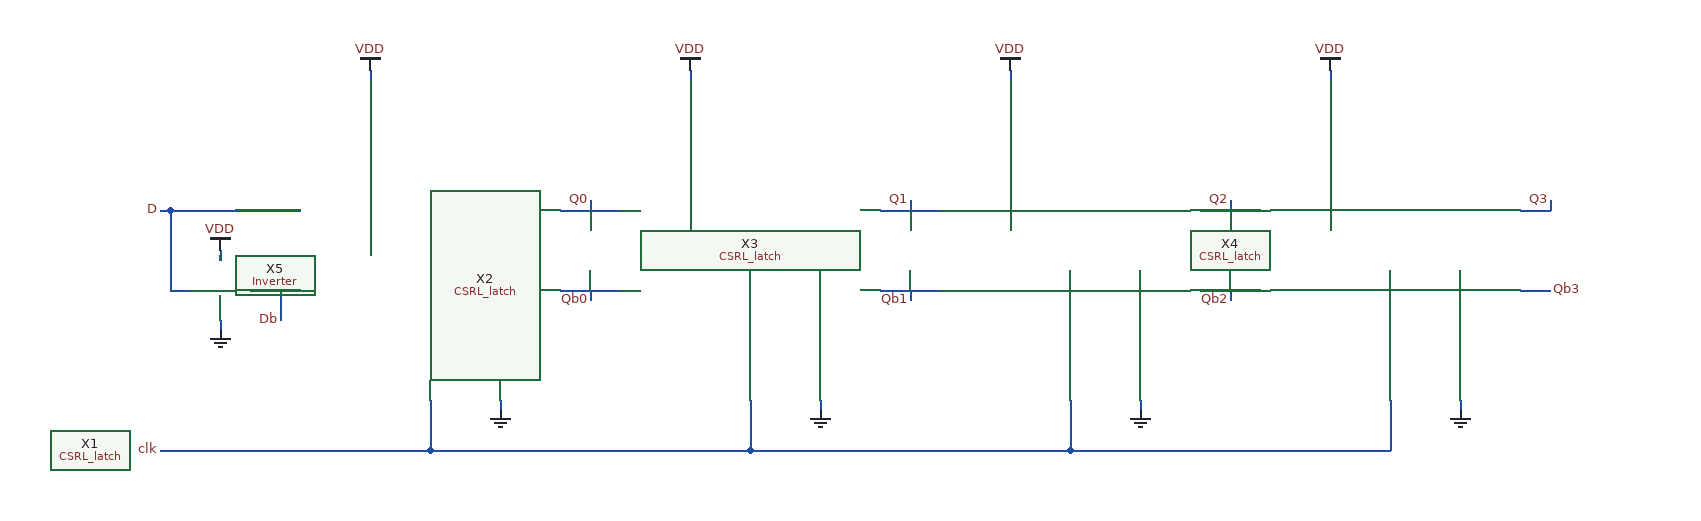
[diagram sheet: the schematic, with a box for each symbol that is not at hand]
v {xschem version=2.9.9 file_version=1.2 }
G {}
K {}
V {}
S {}
E {}
N 280 -440 320 -440 { lab=Db}
N 270 -440 280 -440 { lab=Db}
N 300 -440 300 -410 { lab=Db}
N 190 -440 210 -440 { lab=D}
N 240 -480 240 -470 { lab=VDD}
N 240 -410 240 -400 { lab=GND}
N 190 -520 190 -440 { lab=D}
N 190 -520 320 -520 { lab=D}
N 180 -520 190 -520 { lab=D}
N 580 -440 640 -440 { lab=Qb0}
N 610 -440 610 -430 { lab=Qb0}
N 580 -520 640 -520 { lab=Q0}
N 610 -530 610 -520 { lab=Q0}
N 390 -660 390 -650 { lab=VDD}
N 710 -660 710 -650 { lab=VDD}
N 520 -330 520 -320 { lab=GND}
N 840 -330 840 -320 { lab=GND}
N 180 -280 450 -280 { lab=clk}
N 450 -330 450 -280 { lab=clk}
N 450 -280 770 -280 { lab=clk}
N 770 -330 770 -280 { lab=clk}
N 900 -440 960 -440 { lab=Qb1}
N 930 -440 930 -430 { lab=Qb1}
N 900 -520 960 -520 { lab=Q1}
N 930 -530 930 -520 { lab=Q1}
N 1030 -660 1030 -650 { lab=VDD}
N 1160 -330 1160 -320 { lab=GND}
N 1090 -330 1090 -280 { lab=clk}
N 1220 -440 1280 -440 { lab=Qb2}
N 1250 -440 1250 -430 { lab=Qb2}
N 1220 -520 1280 -520 { lab=Q2}
N 1250 -530 1250 -520 { lab=Q2}
N 1350 -660 1350 -650 { lab=VDD}
N 1480 -330 1480 -320 { lab=GND}
N 1410 -330 1410 -280 { lab=clk}
N 770 -280 1090 -280 { lab=clk}
N 1090 -280 1410 -280 { lab=clk}
N 1570 -530 1570 -520 { lab=Q3}
N 1540 -520 1570 -520 { lab=Q3}
N 1540 -440 1570 -440 { lab=Qb2}
C {/home/madvlsi/Documents/Mini_Project_2/CSRL_latch.sym} 110 -280 0 0 {name=X1}
C {/home/madvlsi/Documents/Mini_Project_2/CSRL_latch.sym} 430 -280 0 0 {name=X2}
C {/home/madvlsi/Documents/Mini_Project_1/Inverter.sym} 180 -440 0 0 {name=X5}
C {devices/lab_pin.sym} 300 -410 3 0 {name=l1 sig_type=std_logic lab=Db}
C {devices/lab_pin.sym} 180 -520 0 0 {name=l2 sig_type=std_logic lab=D}
C {madvlsi/vdd.sym} 240 -480 0 0 {name=l3 lab=VDD}
C {madvlsi/gnd.sym} 240 -400 0 0 {name=l4 lab=GND}
C {devices/lab_pin.sym} 610 -430 3 0 {name=l5 sig_type=std_logic lab=Qb0}
C {devices/lab_pin.sym} 610 -530 1 0 {name=l6 sig_type=std_logic lab=Q0}
C {madvlsi/vdd.sym} 390 -660 0 0 {name=l7 lab=VDD}
C {madvlsi/vdd.sym} 710 -660 0 0 {name=l8 lab=VDD}
C {madvlsi/gnd.sym} 520 -320 0 0 {name=l9 lab=GND}
C {madvlsi/gnd.sym} 840 -320 0 0 {name=l10 lab=GND}
C {devices/lab_pin.sym} 180 -280 0 0 {name=l11 sig_type=std_logic lab=clk}
C {/home/madvlsi/Documents/Mini_Project_2/CSRL_latch.sym} 750 -280 0 0 {name=X3}
C {devices/lab_pin.sym} 930 -430 3 0 {name=l12 sig_type=std_logic lab=Qb1}
C {devices/lab_pin.sym} 930 -530 1 0 {name=l13 sig_type=std_logic lab=Q1}
C {madvlsi/vdd.sym} 1030 -660 0 0 {name=l14 lab=VDD}
C {madvlsi/gnd.sym} 1160 -320 0 0 {name=l15 lab=GND}
C {/home/madvlsi/Documents/Mini_Project_2/CSRL_latch.sym} 1070 -280 0 0 {name=X4}
C {devices/lab_pin.sym} 1250 -430 3 0 {name=l16 sig_type=std_logic lab=Qb2}
C {devices/lab_pin.sym} 1250 -530 1 0 {name=l17 sig_type=std_logic lab=Q2}
C {madvlsi/vdd.sym} 1350 -660 0 0 {name=l18 lab=VDD}
C {madvlsi/gnd.sym} 1480 -320 0 0 {name=l19 lab=GND}
C {devices/lab_pin.sym} 1570 -440 2 0 {name=l20 sig_type=std_logic lab=Qb3}
C {devices/lab_pin.sym} 1570 -530 1 0 {name=l21 sig_type=std_logic lab=Q3}
